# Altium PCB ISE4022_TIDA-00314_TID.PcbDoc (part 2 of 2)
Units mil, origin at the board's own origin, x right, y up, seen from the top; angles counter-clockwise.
Board outline 4724.41 x 1968.5 mil, 4 copper layers (Layer 1 - Top Layer, Layer 2 - GND, Layer 3 - Power, Layer 4 - Bottom Layer), stack 59 mil thick; 99 components, 62 nets, 309 pads, 290 vias.

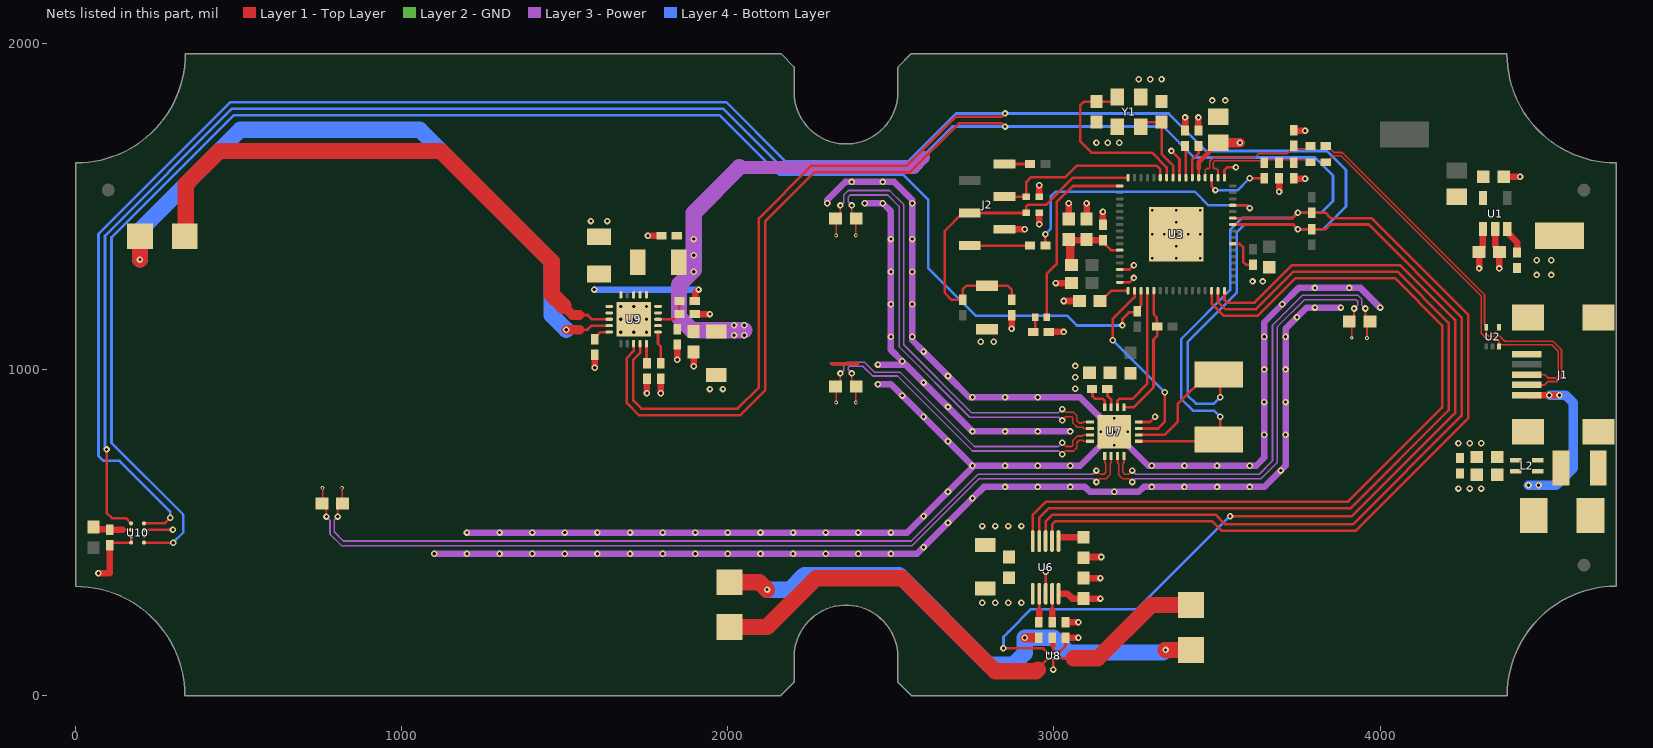
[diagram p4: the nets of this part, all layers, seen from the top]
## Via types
v1: diameter 20, hole 10, Layer 1 - Top Layer to Layer 4 - Bottom Layer, tented bottom, 252 vias
v2: diameter 19.68, hole 7.87, Layer 1 - Top Layer to Layer 4 - Bottom Layer, tented bottom, 18 vias
v3: diameter 12, hole 6, Layer 1 - Top Layer to Layer 4 - Bottom Layer, tented both sides, 17 vias
v4: diameter 20, hole 10, Layer 1 - Top Layer to Layer 4 - Bottom Layer, tented both sides, 3 vias

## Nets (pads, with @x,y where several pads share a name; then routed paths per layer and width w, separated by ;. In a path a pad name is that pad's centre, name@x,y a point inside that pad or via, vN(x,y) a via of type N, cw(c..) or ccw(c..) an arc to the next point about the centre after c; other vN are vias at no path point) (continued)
A1_TX: R8.1 U3.45 | length 849
  Layer 1 - Top Layer w8: R8.1@2973.62,1380 v1(2973.62,1415) ; U3.45@3548.23,1503.58 3591.42,1503.58 v1(3600,1495)
  Layer 4 - Bottom Layer w8: v1(2973.62,1415) 2990,1431.38 2990,1530 3005,1545 3431.72,1545 3473.45,1503.27 3591.73,1503.27 v1(3600,1495)
AVCC: C14.1 C15.2 C16.2 L4.1 U3.11 | length 254.7
  Layer 1 - Top Layer w8: C16.2@3149,1392.38 3149,1391 3174.21,1365.79 U3.11@3201.77,1365.79
  Layer 1 - Top Layer w20: C14.1@3046,1395.5 3047,1396.5 3101,1396.5 3101.13,1396.38 C16.2@3150,1396.38
  Layer 1 - Top Layer w25: C14.1@3046,1395.5 3050,1391.5 3050,1323.5 L4.1@3053.5,1320 ; C15.2@3100,1395.5 C15.2@3101,1396.5 ; C15.2@3101.13,1396.38 C15.2@3105.13,1392.38
B1_SCL: R6.1 SCL.1 U3.43 U6.2 U7.1 U9.18 U10.A1 | length 11230.3
  Layer 1 - Top Layer w8: v1(95,755) 95,560 111.11,543.89 154.57,543.89 U10.A1@170.32,528.14 ; U9.18@1711.06,1079.13 1711.06,1056.06 1690,1035 1690,896.72 1726.72,860 2038.28,860 2115,936.72 2115,1455 2265,1605 2558.28,1605 2708.28,1755 2840,1755 v1(2850,1745) ; U6.2@2994.06,473.75 2994.06,524.06 3005,535 3485,535 3515,505 3925,505 4270,850 4270,1168.28 3974.07,1464.21 3848.51,1464.21 3832,1480.72 R6.1@3790,1480.72 v1(3748,1480.72) 3731.49,1464.21 U3.43@3548.23,1464.21 ; U7.1@3259.8,779.81 SCL.1@3499.81,779.81 ; SCL.1@3505,785 3510,790 v1(3510,855)
  Layer 4 - Bottom Layer w8: v1(95,755) 90,760 90,1410 480,1800 1985,1800 2167,1618 2561.28,1618 2688.28,1745 v1(2850,1745) 3335,1745 3430,1650 3800,1650 3855.48,1594.52 3855.48,1516.21 3820,1480.72 v1(3748,1480.72) 3731.61,1464.34 3576.32,1464.34 3540,1428.02 3540,1243.02 3390.19,1093.21 3390.19,909.81 3426,874 3491,874 v1(3510,855)
B1_SDA: R7.1 SDA.1 U3.42 U6.3 U7.2 U9.19 U10.A2 | length 11518.1
  Layer 1 - Top Layer w8: U10.A2@209.69,528.14 273.14,528.14 v1(290,545) ; U9.19@1730.75,1079.13 1730.75,1050.75 1710,1030 1710,905 1735,880 2030,880 2095,945 2095,1463.28 2256.72,1625 2550,1625 2700,1775 2840,1775 v1(2850,1785) ; U6.3@2974.37,473.75 2974.37,534.37 2995,555 3495,555 3525,525 3916.72,525 4250,858.28 4250,1160 3965.47,1444.53 3846.56,1444.53 3832,1429.97 R7.1@3790,1429.97 v1(3748,1429.97) 3733.44,1444.53 U3.42@3548.23,1444.53 ; U7.2@3259.8,799.5 3339.5,799.5 3380,840 3380,895 3470,985 SDA.1@3505,985 3510,980 v1(3510,915)
  Layer 4 - Bottom Layer w8: v1(290,545) 290,565 135,720 85,720 70,735 70,1415 475,1820 1995,1820 2177,1638 2553,1638 2700,1785 v1(2850,1785) 3351.57,1785 3466.57,1670 3836.57,1670 3895.48,1611.09 3895.48,1500.48 3824.97,1429.97 v1(3748,1429.97) 3733.44,1444.53 3584.53,1444.53 3559.81,1419.81 3559.81,1234.81 3410,1085 3410,920 3435,895 3490,895 v1(3510,915)
D_N: J1.2 R9.1 U2.5 | length 1240.5
  Layer 1 - Top Layer w5.3: R9.1@3841,1682 3857.7,1665.3 3884.27,1665.3 4320.06,1229.51 4320.06,1139 4325.31,1133.74 U2.5@4325.31,1129.53 4325.31,1109.69 4333,1102 4367,1102 4382.7,1086.3 4530.27,1086.3 4556.3,1060.27 4556.3,975.73 4543.97,963.4 4515,963.4 4504.36,952.76 J1.2@4449.76,952.76
D_P: J1.3 R12.2 U2.3 | length 1222.2
  Layer 1 - Top Layer w5.3: R12.2@3838,1636 3857,1655 3880,1655 4309.76,1225.24 4309.76,1110.67 4328.73,1091.7 4360.3,1091.7 4364.69,1087.32 U2.3@4364.69,1070.47 ; U2.3@4365,1076 4526,1076 4546,1056 4546,980 4539.7,973.7 4515,973.7 4504.45,984.25 J1.3@4449.76,984.25
EN_05: U3.30 U6.5 | length 2593.6
  Layer 1 - Top Layer w8: U6.5@2935,473.75 2935,555 2975,595 3901.72,595 4190,883.28 4190,1135 4045,1280 3740,1280 3625,1165 3520,1165 3483.3,1201.7 U3.30@3483.3,1241.77
ERM_OUT-: ERM.- U8.A1 | length 1166.6
  Layer 1 - Top Layer w8: 2953.73,86.27 U8.A1@2981.62,114.17
  Layer 1 - Top Layer w50: ERM.-@2005,210.2 2120.2,210.2 2270,360 2535,360 2820,75 2945,75 2950,80
GND: C2.2 C3.1 C4.1 C5.1 C6.2 C7.2 C8.1 C9.2 C10.2 C11.1 C12.2 C13.2 C14.2 C15.1 C16.1 C17.2 C18.1 C19.1 C20.1 C21.2 C22.1 C24.1 C26.1 C27.1 C29.1 C32.2 C33.1 C34.2 C35.1 C36.1 C37.2 C38.1 C39.1 J2.5 L3.2 R10.1 R13.1 R20.1 R21.2 S1.1 U1.2 U3.14 U3.16 U3.39 U3.49 U3.56 U3.65 U4.2 U5.2 U6.8 U7.4 U7.8 U7.17 U8.B1 U9.4 U9.5 U9.6 U9.21 U10.B2 U10.C1 U10.D1 Y1.2 Y1.4 | length 12582.4
  Layer 1 - Top Layer w8: C38.1@105,461.38 112.71,469.09 U10.D1@170.32,469.09 U10.C1@170.32,488.77 ; U10.B2@209.69,508.46 v1(298.46,508.46) ; U6.8@2974.37,312.33 v1(2974.37,380) ; v1(2997.37,80) U8.B1@2997.37,114.17 ; C27.1@3117,939.17 C27.1@3117.17,939.34 ; C27.1@3118,939.17 3118,918 3126,910 3150,910 3155.47,904.53 U7.8@3155.47,884.14 ; U3.16@3201.77,1267.36 3231.73,1267.36 v1(3245,1280.63) ; U3.14@3201.77,1306.73 3231.73,1306.73 v1(3245,1320) ; U7.4@3259.8,838.87 3293.87,838.87 v1(3310,855) ; v1(3360,1670) 3384.85,1645.15 U3.56@3384.85,1588.23 ; U3.49@3522.68,1588.23 3522.68,1611.68 3531,1620 v1(3558,1620) ; U3.39@3548.23,1385.47 3569.53,1385.47 3580,1375 3580,1330 3588.62,1321.38 C19.1@3610,1321.38
  Layer 1 - Top Layer w10: 2318,1017 2398,1017 ; 2318,1018 2398,1018
  Layer 1 - Top Layer w20: v1(70,375) 105,375 C38.1@105,461.38 ; v1(1592.06,1005) R21.2@1592.06,1045.31 ; v1(1751.85,926.85) C36.1@1751.85,971.6 ; v1(1755,1410) C32.2@1796.38,1410 ; v1(1793.85,926.85) C39.1@1793.85,971.6 ; v1(1845,1030) C35.1@1845,1076.38 ; v1(1895,1010) C34.2@1895,1053.5 ; R20.1@1898.62,1170 v1(1945,1170) ; J2.5@2848.15,1430 v1(2910,1430) ; v1(2870,1125) C11.1@2870,1166.38 ; U4.2@2954.68,1531 v1(2954.68,1564.68) ; v1(2955,1445) U5.2@2955,1479.68 ; R10.1@2983.62,1115 v1(3030,1115) ; v1(3005,1265) C18.1@3053.5,1265 ; v1(3030,1210) C10.2@3078.5,1210 ; C29.1@3035.37,224.67 v1(3075,224.67) ; C14.2@3045,1461.5 v1(3045,1510) ; C22.1@3090.37,360.54 v1(3142.55,360.54) ; C24.1@3090.37,422.55 3092.83,425 v1(3145,425) ; C15.1@3100,1461.5 v1(3100,1510) ; C16.1@3150,1443.62 v1(3150,1484) ; U7.17@3163.74,831.26 3163.74,836.34 3196.18,836.34 3212,820.52 U7.17@3212,809.34 ; C9.2@3402,1732.62 v1(3402,1773) ; C13.2@3443,1732.62 v1(3443,1773) ; v1(3690,1545) R13.1@3690,1586.38 ; C7.2@3735,1586.38 3736.38,1585 v1(3770,1585) ; C6.2@3735,1733.62 3736.38,1732.24 v1(3770,1732.24) ; U1.2@4352.8,1430.78 4352.8,1377.2 4366.5,1363.5 C4.1@4366.5,1360 4365,1358.5 v1(4365,1310) ; C3.1@4379.3,1591.03 v1(4428.97,1591.03)
  Layer 3 - Power w20: v1(1100,435) v1(1200,435) v1(1300,435) v1(1400,435) v1(1500,435) v1(1600,435) v1(1700,435) v1(1800,435) v1(1900,435) v1(2000,435) v1(2100,435) v1(2200,435) v1(2300,435) v1(2400,435) v1(2500,435) 2580,435 v1(2600,455) v1(2675,530) v1(2750,605) 2785,640 v1(2850,640) v1(2950,640) v1(3050,640) 3095,640 3110,625 v1(3185,625) 3260,625 3275,640 v1(3300,640) v1(3400,640) v1(3500,640) v1(3600,640) 3645,640 v1(3695,690) 3710,705 v1(3710,800) v1(3710,900) v1(3710,1000) v1(3710,1100) 3710,1125 v1(3745,1160) 3775,1190 v1(3800,1190) v1(3880,1190) ; v1(1200,500) v1(1300,500) v1(1400,500) v1(1500,500) v1(1600,500) v1(1700,500) v1(1800,500) v1(1900,500) v1(2000,500) v1(2100,500) v1(2200,500) v1(2300,500) v1(2400,500) v1(2500,500) 2550,500 v1(2600,550) v1(2675,625) 2755,705 v1(2850,705) v1(2950,705) v1(3050,705) 3080.66,705 v2(3185,809.34) 3289.34,705 v1(3300,705) v1(3400,705) v1(3500,705) v1(3600,705) 3620,705 3645,730 v1(3645,800) v1(3645,900) v1(3645,1000) v1(3645,1100) 3645,1145 v1(3700,1200) 3750,1250 v1(3800,1250) v1(3905,1250) 3940,1250 v1(4000,1190) ; v1(2305,1510) 2305,1520 2360,1575 v1(2380,1575) v1(2475,1575) 2510,1575 2565,1520 v1(2565,1510) v1(2565,1400) v1(2565,1300) v1(2565,1200) v1(2565,1100) 2565,1090 v1(2600,1055) v1(2675,980) 2740,915 v1(2750,915) v1(2850,915) v1(2950,915) 3080,915 v2@3185.33,809.67 ; v1(2420,1510) v1(2475,1510) 2500,1485 v1(2500,1400) v1(2500,1300) v1(2500,1200) v1(2500,1100) 2500,1060 v1(2535,1025) 2545,1015 ; v1(2460,955) 2500,955 v1(2535,920) v1(2600,855) v1(2675,780) v1(2750,705) ; v1(2460,1015) 2545,1015 ; v1(3050,810) v1(2950,810) v1(2850,810) v1(2750,810) v1(2675,885) v1(2600,960) 2545,1015
  Layer 2 - GND w10: 2325,1017 2395,1017 ; 2325,1018 2395,1018
  Layer 4 - Bottom Layer w10: 2317,1018 2397,1018
  other v1: 2780,520 2820,520 2860,520 2900,520 4240,774 4275,774 4310,774 1945,940 1985,940 3065.5,941 3065.5,976 3065.5,1011 2775,1085 2815,1085 1671.69,1114.57 1711.06,1114.57 1750.43,1114.57 1671.69,1153.94 1711.06,1153.94 1750.43,1153.94 1671.69,1193.31 1711.06,1193.31 1750.43,1193.31 3609,1270 3640,1270 1580,1455 1630,1455 3130,1695 3165,1695 3200,1695 3485,1825 3525,1825 3260,1890 3295,1890 3330,1890
  other v2: 3185,768 3143.66,809.34 3226.34,809.34 3185,850.68 3301.18,1341.18 3375,1341.18 3448.82,1341.18 3375,1378.09 3301.18,1415 3338.09,1415 3375,1415 3411.91,1415 3448.82,1415 3375,1451.91 3301.18,1488.82 3375,1488.82 3448.82,1488.82
IN0A: C30.1 U7.9 | length 1462.1
  Layer 1 - Top Layer w5: v3(2332.2,1411.16) 2332.2,1461.3 C30.1@2330.5,1463 2345,1477.5 v1(2345,1503) ; v1(3025,878.68) 3035,868.68 3060,868.68 3070,858.68 3070,843.48 3077.77,835.71 3087.03,835.71 3090.19,838.87 U7.9@3110.2,838.87
  Layer 3 - Power w5: v1(2345,1503) 2355,1513 2355,1534.8 2369.2,1549 2495.8,1549 2539,1505.8 2539,1076 2747.32,867.68 3014,867.68 v1(3025,878.68)
IN0B: C30.2 U7.10 | length 1438.4
  Layer 1 - Top Layer w5: v1(2380,1503) 2380,1476.5 C30.2@2393.5,1463 2392.2,1461.71 v3(2392.2,1411.16) ; v1(3025,843.68) 3036,854.68 3054,854.68 3058,850.68 3058,835.68 3070.97,822.71 3086.66,822.71 3090.19,819.18 U7.10@3110.2,819.18
  Layer 3 - Power w5: v1(2380,1503) 2369,1514 2369,1529 2375,1535 2490,1535 2525,1500 2525,1070.2 2741.52,853.68 3015,853.68 v1(3025,843.68)
IN1A: C28.1 U7.11 | length 1019.8
  Layer 1 - Top Layer w5: C28.1@2330.5,948 2345,962.5 v1(2345,988) ; v3(2332.2,899.35) C28.1@2332.2,946.3 ; v1(3025,775) 3036,764 3054,764 3058,768 3058,783 3070.97,795.97 3086.66,795.97 3090.19,799.5 U7.11@3110.2,799.5
  Layer 3 - Power w5: v1(2345,988) 2355,998 2355,1011.8 2365.2,1022 2418.97,1022 2448.97,992 2528,992 2756,764 3014,764 v1(3025,775)
IN1B: C28.2 U7.12 | length 998.2
  Layer 1 - Top Layer w5: v1(2380,988) 2380,961.5 C28.2@2393.5,948 ; v3(2392.2,899.35) C28.2@2392.2,946.71 ; v1(3025,740) 3035,750 3060,750 3070,760 3070,775.2 3077.77,782.97 3087.03,782.97 3090.19,779.81 U7.12@3110.2,779.81
  Layer 3 - Power w5: v1(2380,988) 2369,999 2369,1006 2373,1010 2414,1010 2444,980 2520.2,980 2750.2,750 3015,750 v1(3025,740)
IN2A: C25.1 U7.13 | length 2671.4
  Layer 1 - Top Layer w5: v1(804,549) 804,574.5 C25.1@818.5,589 817.4,590.09 v3(817.4,637.25) ; v1(3130,690) 3141,679 3153,679 3159,685 3159,711 3155.47,714.53 U7.13@3155.47,734.54
  Layer 3 - Power w5: v1(804,549) 793,538 793,502 821,474 2562.03,474 2767.03,679 3119,679 v1(3130,690)
IN2B: C25.2 U7.14 | length 2716.7
  Layer 1 - Top Layer w5: v3(757.4,637.25) 757.4,590.9 C25.2@755.5,589 769,575.5 v1(769,549) ; v1(3130,655) 3140,665 3160,665 3172,677 3172,711.37 3175.16,714.53 U7.14@3175.16,734.54
  Layer 3 - Power w5: v1(769,549) 780,538 780,495 815,460 2565,460 2770,665 3120,665 v1(3130,655)
IN3A: C31.1 U7.15 | length 1403.6
  Layer 1 - Top Layer w5: U7.15@3194.84,734.54 3194.84,714.53 3198.37,711 3198.37,676.63 3210,665 3230,665 v1(3240,655) ; v3(3913.01,1097.25) 3913.01,1139.5 C31.1@3905.5,1147 3920,1161.5 v1(3920,1187)
  Layer 3 - Power w5: v1(3240,655) 3250,665 3634.8,665 3684,714.2 3684,1130 3768,1214 3926,1214 3931,1209 3931,1198 v1(3920,1187)
IN3B: C31.2 U7.16 | length 1404.8
  Layer 1 - Top Layer w5: U7.16@3214.53,734.54 3214.53,714.53 3211.37,711.37 3211.37,684.63 3217,679 3229,679 v1(3240,690) ; v1(3955,1187) 3955,1160.5 C31.2@3968.5,1147 3959.88,1138.38 v3(3959.88,1096.12)
  Layer 3 - Power w5: v1(3240,690) 3251,679 3629,679 3670,720 3670,1135.8 3762.2,1228 3932,1228 3944,1216 3944,1198 v1(3955,1187)
IN_SW: U3.32 U8.A2 | length 2989.4
  Layer 1 - Top Layer w8: v1(2845,145) 2966.54,145 2981.54,130 U8.A2@2981.62,129.92 ; U3.32@3522.68,1241.77 3522.68,1212.32 3530,1205 3615,1205 3730,1320 4061.57,1320 4230,1151.57 4230,866.72 3913.28,550 v1(3540,550)
  Layer 4 - Bottom Layer w8: v1(2845,145) 2845,180 2860,195 2930,265 3255,265 v1(3540,550)
IN_TRIG_05: U3.31 U6.4 | length 2594.8
  Layer 1 - Top Layer w8: U6.4@2954.69,473.75 2954.69,544.69 2985,575 3910,575 4210,875 4210,1143.28 4053.28,1300 3735,1300 3620,1185 3525,1185 3502.99,1207.01 U3.31@3502.99,1241.77
LDC_CLKIN: U3.18 U7.3 | length 584.6
  Layer 1 - Top Layer w8: v1(3180,1090) 3180,1155 3247.02,1222.02 U3.18@3247.02,1241.77 ; U7.3@3259.8,819.18 3319.18,819.18 3340,840 v1(3340,930)
  Layer 4 - Bottom Layer w8: v1(3180,1090) v1(3340,930)
LDC_INTB: R4.1 U3.21 U7.5 | length 424.3
  Layer 1 - Top Layer w8: U7.5@3214.53,884.14 3244.14,884.14 3305,945 3305,1091.65 3316.38,1103.03 R4.1@3316.38,1131.65 R4.1@3315,1130.28 ; U3.21@3305,1240.69 U3.21@3306.09,1241.77 3306.09,1168.91 3315,1160 R4.1@3315,1131.65
LDC_SD: U3.20 U7.6 | length 418.8
  Layer 1 - Top Layer w8: U7.6@3194.84,884.14 3194.84,904.53 3200.31,910 3240,910 3286.4,956.4 U3.20@3286.4,1241.77
LRA_OUT-: LRA.- U8.C1 | length 432.3
  Layer 1 - Top Layer w8: U8.C1@3013.12,114.17 3060,114.17
  Layer 1 - Top Layer w50: 3060,114.17 3134.17,114.17 3297.8,277.8 3377.63,277.8
MSP_D_N: C6.1 R9.2 U3.52 | length 388
  Layer 1 - Top Layer w5.3: U3.52@3463.61,1588.23 3463.61,1611.61 3468,1616 3475,1616 3478,1619 3478,1638.57 3489.43,1650 3615,1650 3627,1662 3714,1662 3729,1677 3778.38,1677 R9.2@3786.38,1685
MSP_D_P: C7.1 R11.2 R12.1 R13.2 U3.50 | length 366
  Layer 1 - Top Layer w5.3: U3.50@3502.99,1588.23 3502.99,1611.61 3498.59,1616 3491.59,1616 3488.59,1619 3488.59,1634.59 3493.7,1639.7 3638.92,1639.7 R11.2@3645,1633.62 3654.38,1643 3778.38,1643 R12.1@3786.38,1635
NDRDY_HDC: R3.1 U3.19 U10.D2 | length 4911.2
  Layer 1 - Top Layer w8: U10.D2@209.69,469.09 v1(299.09,469.09) ; v1(3210,1135) 3210,1155 3230,1175 3251.38,1175 R3.1@3255,1178.62 ; R3.1@3255,1185 3266.71,1196.71 U3.19@3266.71,1241.77
  Layer 4 - Bottom Layer w8: v1(299.09,469.09) 330,500 330,555 110,775 110,1405 485,1780 1975,1780 2157,1598 2537,1598 2615,1520 2615,1310 2760,1165 3040,1165 3070,1135 v1(3210,1135)
NetC3_2: C3.2 R1.1 U1.5
NetC24_2: C24.2 U6.1 | length 72.4
  Layer 1 - Top Layer w20: U6.1@3018,485.54 C24.2@3090.37,485.54
NetC26_2: C26.2 C27.2 L6.2 U7.7 | length 60.5
  Layer 1 - Top Layer w8: C27.2@3164,940 3164,919.38 3175.16,908.22 U7.7@3175.16,884.14
NetC36_2: C36.2 U9.20 | length 60.9
  Layer 1 - Top Layer w8: U9.20@1750.43,1079.13 1750.43,1020.26 C36.2@1751.85,1018.84
NetC37_1: C37.1 R19.2 U9.10 U9.11 U9.12 | length 360.5
  Layer 1 - Top Layer w8: R19.2@1898.62,1210 R19.2@1900,1210
  Layer 1 - Top Layer w20: R19.2@1900,1210 1900,1235 v1(1910,1245)
  Layer 4 - Bottom Layer w20: v1(1590,1245) v1(1910,1245)
NetC38_2: C38.2 L7.1 U10.B1 | length 118.8
  Layer 1 - Top Layer w8: 145,508.46 U10.B1@170.32,508.46
  Layer 1 - Top Layer w20: L7.1@55,517.48 62.48,510 103.62,510 C38.2@105,508.62 ; C38.2@105.17,508.46 145,508.46
NetC39_2: C39.2 U9.1 | length 99
  Layer 1 - Top Layer w8: U9.1@1785.87,1114.57 1785.87,1079.13 1793.85,1071.15 C39.2@1793.85,1018.84
NetD2_1: D2.1 U3.1 | length 579.9
  Layer 1 - Top Layer w8: D2.1@2977.72,1160 2977.72,1292.72 3008,1323 3008,1513 3057.64,1562.64 U3.1@3201.77,1562.64
NetD2_2: D2.2 R10.2 | length 47.4
  Layer 1 - Top Layer w8: R10.2@2936.38,1115 2942.28,1120.91 D2.2@2942.28,1160
NetJ2_1: J2.1 R5.2 | length 78.2
  Layer 1 - Top Layer w8: J2.1@2848.15,1630 R5.2@2926.38,1630
NetJ2_6: J2.6 R8.2 | length 184.5
  Layer 1 - Top Layer w8: J2.6@2741.85,1380 R8.2@2926.38,1380
NetL1_1: L1.1 L2.2
NetL2_3: L2.3 L3.1
NetL5_1: L5.1 U9.7 U9.8
NetR2_1: R2.1 U1.3 | length 84.5
  Layer 1 - Top Layer w8: U1.3@4390.21,1419.79 U1.3@4390.21,1430.78
  Layer 1 - Top Layer w20: U1.3@4390.21,1419.79 4420,1390 R2.1@4420,1358.62
NetR15_1: R15.1 U6.7 | length 89.2
  Layer 1 - Top Layer w8: R15.1@2953.37,224.67 R15.1@2954.69,225.98 ; 2954.69,260.94 U6.7@2954.69,312.33
  Layer 1 - Top Layer w20: R15.1@2954.69,224.98 2954.69,225.98 2954.69,260.94
NetR18_1: R18.1 U6.9 | length 87.4
  Layer 1 - Top Layer w8: 2994.06,260.94 U6.9@2994.06,312.33
  Layer 1 - Top Layer w20: R18.1@2994.06,224.98 2994.06,260.94
NetR19_1: R19.1 R20.2 U9.3 | length 103.7
  Layer 1 - Top Layer w8: U9.3@1785.87,1153.94 1833.94,1153.94 R20.2@1845,1165 ; R20.2@1851.38,1170 R19.1@1851.38,1210
NetR21_1: R21.1 U9.15 | length 57.9
  Layer 1 - Top Layer w8: R21.1@1592.06,1090.57 R21.1@1592.06,1092.56 1592.06,1097.06 1609.57,1114.57 U9.15@1636.26,1114.57
OUT+_05: ERM.+ LRA.+ R15.2 | length 1681.1
  Layer 1 - Top Layer w30: v1(2910,177.42) R15.2@2950,177.42
  Layer 1 - Top Layer w50: ERM.+@2005,348 2097,348 v1(2120,325) ; v1(3342,140) LRA.+@3420,140
  Layer 4 - Bottom Layer w50: v1(2120,325) 2190,325 2235,370 2525,370 2800,95 2875,95 2910,130 v1(2910,177.42) 2998.33,177.42 3043.75,132 3334,132 v1(3342,140)
OUT+_67: Piezo.+ U9.13 | length 1774.7
  Layer 1 - Top Layer w8: 1545.06,1166.94 1570.06,1166.94 1583.06,1153.94 U9.13@1636.26,1153.94
  Layer 1 - Top Layer w30: 1495,1195 1523.06,1166.94 1545.06,1166.94
  Layer 1 - Top Layer w50: Piezo.+@337.68,1406.32 337.68,1567.68 440,1670 1120,1670 1460,1330 1460,1230 1495,1195
OUT-_05: R18.2 U8.B2 | length 48.7
  Layer 1 - Top Layer w8: U8.B2@2997.37,129.92 2997.37,151.63
  Layer 1 - Top Layer w15: R18.2@2994.37,177.42 2997.37,174.42 2997.37,151.63
OUT-_67: Piezo.- U9.14 | length 2083.2
  Layer 1 - Top Layer w8: 1545.06,1121.94 1570.06,1121.94 1582.38,1134.25 U9.14@1636.26,1134.25
  Layer 1 - Top Layer w30: v1(1504.42,1121.94) 1545.06,1121.94
  Layer 1 - Top Layer w50: v1(197.2,1337.2) Piezo.-@197.2,1409
  Layer 4 - Bottom Layer w50: v1(197.2,1337.2) 197.2,1427.2 505,1735 1055,1735 1460,1330 1460,1166.36 v1(1504.42,1121.94)
PUR: R11.1 U3.51 | length 208.1
  Layer 1 - Top Layer w8: U3.51@3483.3,1588.23 3483.3,1561.7 v1(3495,1550) ; v1(3600,1586.38) R11.1@3645,1586.38
  Layer 4 - Bottom Layer w8: v1(3495,1550) 3563.62,1550 v1(3600,1586.38)
SBWTCK: J2.3 U3.59 U4.1 | length 575.6
  Layer 1 - Top Layer w8: J2.3@2846.54,1529.99 U4.1@2915.32,1530 2915.3,1575.3 2930,1590 3035,1590 3070,1625 3315,1625 3325.78,1614.22 U3.59@3325.78,1588.23
SBWTDIO: C11.2 J2.4 R14.1 S1.2 U3.64 U5.1 | length 1118.3
  Layer 1 - Top Layer w8: C11.2@2870,1213.62 2870,1245 2858.07,1256.93 S1.2@2795,1256.93 2731.93,1256.93 2720,1245 R14.1@2720,1213.62 2686.38,1213.62 2665,1235 2665,1425 2720,1480 J2.4@2741.85,1480 U5.1@2915.32,1480 2915.32,1500.32 2920,1505 2975,1505 3058.23,1588.23 U3.64@3227.33,1588.23
USB_GND: C1.2 D1.1 J1.5 J1.6 J1.7 J1.8 J1.9 L2.4 U2.4
V18: C9.1 U3.55 | length 98.2
  Layer 1 - Top Layer w8: C9.1@3402,1685.38 3404.54,1682.84 U3.55@3404.54,1588.23
VBUS: C1.1 D1.2 J1.1 L2.1 | length 541.4
  Layer 1 - Top Layer w20: J1.1@4449.76,921.26 4520,921.26 v1(4550,921.26)
  Layer 4 - Bottom Layer w30: v1(4455,645) 4485,645 4539.31,645 4592.5,698.18 4592.5,897.5 4568.74,921.26 v1(4550,921.26) v1@4520,921.26
  other v1: 4486,645 4519,921.26
VBUS_FLT: C2.1 C4.2 C12.1 C20.2 C21.1 C22.2 C29.2 C32.1 C33.2 C34.1 C35.2 L1.2 L5.2 R2.2 U1.1 U3.53 U6.6 U6.10 U8.C2 U9.2 VBUS_FLT.1 | length 1870
  Layer 1 - Top Layer w8: U8.C2@3013.12,129.92 3035.37,152.17 C29.2@3035.37,177.42 ; U6.10@3013.74,312.33 U6.10@3014.41,313 ; U3.53@3443.92,1588.23 3443.92,1616.92
  Layer 1 - Top Layer w15: 3443.92,1616.92 3443.92,1635.92 3503,1695 C12.1@3504,1695
  Layer 1 - Top Layer w20: U6.10@3018,313 3041,313 3056.45,297.55 C22.2@3090.37,297.55 v1(3142.45,297.55) ; C29.2@3035.37,177.42 v1(3075,177.42) ; v1(4303.5,1310) C4.2@4303.5,1360 ; C4.2@4310,1370 4315.4,1375.4 U1.1@4315.4,1430.78
  Layer 1 - Top Layer w30: C12.1@3504,1695 v1(3570,1695)
  Layer 3 - Power w40: 2035,1620 2570,1620 2600,1650
  Layer 3 - Power w50: 2035,1620 1895,1480 v1(1895,1400) v1(1895,1350) 1895,1305 1850,1260 1850,1160 1890,1120 2050,1120
  other v1: 2780,285 2820,285 2860,285 2900,285 4240,635 4275,635 4310,635 2019,1105 2050,1105 2019,1136 2050,1136 4480,1290 4525,1290 1895,1300 4480,1335 4525,1335
VCORE: C10.1 U3.17 | length 81.3
  Layer 1 - Top Layer w8: C10.1@3155,1220 3176.77,1241.77 U3.17@3227.33,1241.77
VUSB: C13.1 U3.54 | length 104.9
  Layer 1 - Top Layer w8: U3.54@3424.23,1588.23 3424.23,1644.23 3443,1663 C13.1@3443,1685.38
XT2IN: C5.2 U3.57 Y1.1 | length 254.1
  Layer 1 - Top Layer w8: Y1.1@3266.42,1744.72 3280.2,1758.5 C5.2@3330,1758.5 3330,1660 3365.16,1624.84 U3.57@3365.16,1588.23
XT2OUT: C8.2 U3.58 Y1.3 | length 564.2
  Layer 1 - Top Layer w8: Y1.3@3193.58,1835.28 3179.8,1821.5 C8.2@3130,1821.5 3091.5,1821.5 3080,1810 3080,1700 3115,1665 3300,1665 3345.47,1619.53 U3.58@3345.47,1588.23
pads on no net: FID1.1 FID2.1 FID3.1 J1.4 U1.4 U2.1 U2.2 U3.2 U3.3 U3.4 U3.5 U3.6 U3.7 U3.8 U3.9 U3.10 U3.12 U3.13 U3.22 U3.23 U3.24 U3.25 U3.26 U3.27 U3.28 U3.29 U3.33 U3.34 U3.35 U3.36 U3.37 U3.38 U3.41 U3.44 U3.47 U3.48 U3.60 U3.61 U3.62 U3.63 U9.9 U9.16 U9.17 U10.C2
copper on no net:
  other v3: 2362.2,709.35 2362.2,739.35 2362.2,899.35 3937.01,969.25 3937.01,991.25 3937.01,1099.25 2362.2,1221.16 2362.2,1251.16 2362.2,1411.16
  other v4: 787.4,651.25 787.4,973.25 787.4,1003.25

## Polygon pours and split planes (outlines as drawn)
GND on Layer 2 - GND "Layer 2 - GND- GND" (solid, remove dead copper, pour order 13): 0,0 4724.41,0 4724.41,1967.91 4725,1968.5 -0.5,1968.5 -1,1969
GND on Layer 3 - Power "Layer 2 - GND- GND" (solid, remove dead copper, pour order 12): 0,0 4724.41,0 4724.41,1967.91 4725,1968.5 -0.5,1968.5 -1,1969
VBUS_FLT on Layer 3 - Power "Layer 3 - Power- VBUS_FLT" (solid, pour order 9): 2765,280 2765,320 2785,340 2980,340 3015,375 3040,400 3175,400 3195,420 3210,435 3240,435 3840,435 3900,495 4275,870 4275,945 4275,1565 4180,1660 4155,1685 3920,1685 3500,1685 3440,1625 2580,1625 2580,1740 2660,1820 2705,1865 4230,1865 4455,1640 4595,1500 4595,1105 4595,845 4380,630 3915,165 3215,165 3025,165 2980,210 2785,210 2765,230 2765,280 2765,320
GND on Layer 1 - Top Layer "Layer 2 - GND- GND" (solid, remove dead copper, pour order 11): 0,0 4724.41,0 4724.41,1967.91 4725,1968.5 -0.5,1968.5 -1,1969
GND on Layer 4 - Bottom Layer "Layer 2 - GND- GND" (solid, remove dead copper, pour order 10): 0,0 4724.41,0 4724.41,1967.91 4725,1968.5 -0.5,1968.5 -1,1969

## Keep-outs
Keep-Out Layer:
  lines w4: 2161.42,0 335.17,0 ccw(c0.52,0) 0,334.65 0,1633.36 ccw(c1.52,1968) 336.17,1968.5 2162.5,1968.5 2203.15,1927.85 2203.15,1850.39 ccw(c2362.2,1850.39) 2521.26,1850.39 2521.26,1927.26 2562.5,1968.5 4388.83,1968.5 ccw(c4723.48,1968) 4724.41,1633.36 ; 2162,0 2203.15,41.15 2203.15,118.11 cw(c2362.2,118.11) 2521.26,118.11 2521.26,40.74 2562,0 4389.84,0 cw(c4724.48,1) 4724.41,335.65
  text ".Layer_Name" at 577,-858.49 h60

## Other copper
Layer 1 - Top Layer:
  region: 182,532 198,532 198,465 182,465
  region net VBUS_FLT: 4405,1330 4450,1330 4470,1350 4470,1455 4630,1455 4630,1320 4575,1265 4425,1265 4405,1285
  region net GND: 1745,1241 1776,1241 1798,1219 1798,1168 1745,1168
  pour cut-out: 2913.35,357.61 2913.35,428.48 3033.48,428.48 3035,430 3035.4,429.6 3035.4,357.61
  pour cut-out: 3160,1790 3295,1790 3295,1810 3245,1810 3245,1875 3230,1875 3230,1810 3160,1810
  pour cut-out: 3175,1215 3575,1215 3575,1595 3175,1595
  pour cut-out: 1615,1085 1810,1085 1810,1270 1615,1270
  pour cut-out: 2238,1023 2238,1027 2482,1027 2482,1453 2242,1453 2242,1027 2238,1027 2238,1457 2486,1457 2486,1023 2459,1023 2254,1023 2242,1023
  pour cut-out: 2238,511.19 2238,515.19 2482,515.19 2482,941.19 2242,941.19 2242,515.19 2238,515.19 2238,945.19 2486,945.19 2486,511.19 2459,511.19 2254,511.19 2242,511.19
  pour cut-out: 325,410 325,470 290,505 290,515 310,535 310,560 275,595 45,595 45,410
  region net VBUS_FLT: 1825,1285 1910,1285 1910,1425 1825,1425
  region net GND: 1645,1380 1645,1470 1565,1470 1565,1380
  region net VBUS_FLT: 1774,1140 2060,1140 2060,1095 1875,1095 1865,1105 1830,1105 1806,1129 1774,1129
  region net GND: 1930,1005 1930,925 2000,925 2000,1005
  region net NetL5_1: 1706,1217 1706,1253 1695,1264 1695,1369 1747,1369 1747,1264 1736,1253 1736,1217
  region net NetC37_1: 1648,1169 1648,1211 1654,1217 1677,1217 1677,1288 1645,1320 1565,1320 1565,1199 1595,1169
  region net GND: 2915,400 2915,525 2905,535 2775,535 2755,515 2755,425 2780,400
  region net VBUS_FLT: 2908,385 2941,352 2941,282 2929,270 2765,270 2755,280 2755,360 2780,385
  region net GND: 3135,925 3135,1015 3050,1015 3050,925 3112.05,925 3114,923.05 3122.03,923.05 3124.03,925
  region net NetC26_2: 3145,925 3158,925 3160,923 3168,923 3170,925 3210,925 3254,969 3254,1015 3145,1015
  region net 3V3: 3095,1340 3160,1340 3175,1325 3175,1297 3182,1290 3182,1284 3175,1277 3175,1260 3160,1245 3095,1245
  region net GND: 3595,1340 3680,1340 3680,1295 3645,1260 3605,1260 3595,1270 3595,1307 3595,1310 3595,1311 3595,1313 3595,1316 3593,1318 3593,1325 3595,1327 3595,1328
  region net 3V3: 3580,1402 3597,1385 3597,1352 3680,1352 3680,1415 3667,1428 3599,1428 3580,1409
  region net GND: 2830,1140 2760,1140 2760,1070 2830,1070
  region net GND: 3350,1800 3245,1800 3245,1900 3335,1900 3350,1885
  region net GND: 3110,1780 3215,1780 3215,1680 3125,1680 3110,1695
  region net GND: 3470,1750 3540,1750 3540,1835 3470,1835
  region net USB_GND: 4695,495 4695,745 4720,770 4720,1200 4395,1200 4355,1160 4355,1115 4540,1115 4580,1075 4580,920 4555,895 4390,895 4375,910 4375,1019 4393,1037 4496,1037 4496,1060 4380,1060 4365,1045 4355,1045 4330,1045 4310,1025 4310,990 4310,850 4395,765 4425,765 4455,735 4455,710 4510,710 4510,750 4525,765 4585,765 4600,750 4600,495
  region net VBUS: 4455,700 4520,700 4525,705 4525,752 4581,752 4581,551 4525,495 4425,495 4425,650 4455,680
  region net NetL2_3: 4440,710 4440,735 4420,755 4335,755 4335,710
  region net NetL1_1: 4440,700 4335,700 4335,655 4415,655 4440,680
  region net VBUS_FLT: 4320,700 4320,625 4310,615 4240,615 4230,625 4230,700
  region net GND: 4320,709 4320,784 4310,794 4240,794 4230,784 4230,709
  region net NetC3_2: 4200,1500 4330,1500 4340,1510 4340,1615 4295,1615 4295,1580 4275,1560 4200,1560
  region net 3V3: 4270,1585 4040,1585 4000,1625 4000,1760 4225,1760 4270,1715
  text ".Layer_Name" at 577,-858.49 h60
Layer 3 - Power:
  region net GND: 2490,1065 2490,1025 2530,1025
  pour cut-out: 325,410 325,470 290,505 290,515 310,535 310,560 275,595 45,595 45,410
  pour cut-out: 2238,1023 2238,1027 2482,1027 2482,1453 2242,1453 2242,1027 2238,1027 2238,1457 2486,1457 2486,1023 2459,1023 2254,1023 2242,1023
  pour cut-out: 2238,511.19 2238,515.19 2482,515.19 2482,941.19 2242,941.19 2242,515.19 2238,515.19 2238,945.19 2486,945.19 2486,511.19 2459,511.19 2254,511.19 2242,511.19
Layer 2 - GND:
  pour cut-out: 325,410 325,470 290,505 290,515 310,535 310,560 275,595 45,595 45,410
  pour cut-out: 2238,511.19 2238,515.19 2482,515.19 2482,941.19 2242,941.19 2242,515.19 2238,515.19 2238,945.19 2486,945.19 2486,511.19 2459,511.19 2254,511.19 2242,511.19
  pour cut-out: 2238,1023 2238,1027 2482,1027 2482,1453 2242,1453 2242,1027 2238,1027 2238,1457 2486,1457 2486,1023 2459,1023 2254,1023 2242,1023
Layer 4 - Bottom Layer:
  pour cut-out: 2238,1023 2238,1027 2482,1027 2482,1453 2242,1453 2242,1027 2238,1027 2238,1457 2486,1457 2486,1023 2459,1023 2254,1023 2242,1023
  pour cut-out: 2238,511.19 2238,515.19 2482,515.19 2482,941.19 2242,941.19 2242,515.19 2238,515.19 2238,945.19 2486,945.19 2486,511.19 2459,511.19 2254,511.19 2242,511.19
  pour cut-out: 325,410 325,470 290,505 290,515 310,535 310,560 275,595 51,595 51,410
  text ".Layer_Name" at 577,-858.49 h60

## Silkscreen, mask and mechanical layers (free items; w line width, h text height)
Top Overlay:
  circle w12: c4180,379 r196.85
  lines w7.01: 373,1511 2123.13,1511 ; 373,1512 373,1738.54 ; 374,1738.27 2123.13,1738.27 2123.13,1512 ; 922.56,144.2 922.56,419.8 1867.44,419.8 1867.44,144.2 922.56,144.2
  text "For evaluation only; not FCC approved for resale" at 567,1830 h75
  text ".TID" at 1385,25 h100
  text ".PRJ_Number" at 3224,25 h100
  text ".PCB_Rev" at 3610,25 h100
  text ".Layer_Name" at 577,-858.49 h60
Bottom Overlay:
  text ".Layer_Name" at 577,-858.49 h60
Top Paste:
  text ".Layer_Name" at 577,-858.49 h60
Bottom Paste:
  text ".Layer_Name" at 577,-858.49 h60
Top Solder:
  text ".Layer_Name" at 577,-858.49 h60
  text ".Layer_Name" at 577,-858.49 h60
Bottom Solder:
  lines w100: 0,334.65 cw(c0.52,0) 335.17,0 2161.42,0 ; 0,1633.36 ccw(c1.52,1968) 336.17,1968.5 ; 0.76,335.4 0.76,1632.99 ; 336.54,1968.5 2162.5,1968.5 2203.15,1927.85 2203.15,1850.39 ccw(c2362.2,1850.39) 2521.26,1850.39 2521.26,1927.26 2562.5,1968.5 4388.19,1968.5 ; 2162,0 2203.15,41.15 2203.15,118.11 cw(c2362.2,118.11) 2521.26,118.11 2521.26,40.74 2561,1 4388.48,1 ; 4388.83,1968.5 ccw(c4723.48,1968) 4724.41,1633.36 ; 4389.84,0 cw(c4724.48,1) 4724.41,335.65 ; 4723.48,336.98 4723.48,1632.95
  text ".Layer_Name" at 577,-858.49 h60
Drill Guide:
  text ".Layer_Name" at 577,-858.49 h60
M1 Board Outline:
  lines w4: 2161.42,0 335.17,0 ccw(c0.52,0) 0,334.65 0,1633.36 ccw(c1.52,1968) 336.17,1968.5 2162.5,1968.5 2203.15,1927.85 2203.15,1850.39 ccw(c2362.2,1850.39) 2521.26,1850.39 2521.26,1927.26 2562.5,1968.5 4388.83,1968.5 ccw(c4723.48,1968) 4724.41,1633.36 4724.41,335.65 ccw(c4724.48,1) 4389.84,0 2562,0 2521.26,40.74 2521.26,118.11 ccw(c2362.2,118.11) 2203.15,118.11 2203.15,41.15 2162,0
  text ".Layer_Name" at 577,-858.49 h60
M2 Board Dimensions:
  rectangle: 125,-400 500,-275
  rectangle: 0,-275 125,-150
  lines w5: 165,988 476,988 ; 787,1296 787,1607 ; 1098,988 1409,988 ; 2240,724 2301,724 ; 2240,1235.81 2301,1235.81 ; 2362,513 2362,574 ; 2362,1024.81 2362,1085.81 ; 2362,1394 2362,1455 ; 2423,724 2484,724 ; 2423,1235.81 2484,1235.81 ; 3735,980 3836,980 ; 3937,782 3937,883 ; 4038,980 4139,980
  lines w7: 0,-275 1000,-275 ; 125,-400 125,-150 ; 250,-400 250,-150 ; 500,-400 500,-150 ; 750,-400 750,-150 ; 0,-400 0,-150 1000,-150 1000,-400 0,-400
  text ".Layer_Name" at 577,-858.49 h60
M3 3D STEP Top:
  text ".Layer_Name" at 577,-858.49 h60
M4 3D STEP Bottom:
  text ".Layer_Name" at 577,-858.49 h60
M5 Assembly Top:
  lines w10: -292,-930.17 6308,-930.17 ; -292,-726.83 6310,-726.83 ; -292,-523.5 -292,-1133.5 3713,-1133.5 6310,-1133.5 6310,-523.5 -291.5,-523.5 -291.5,-1133.5 1284,-1133.5 ; 2173,-1133.5 2173,-523.5 ; 3440,-726.83 3440,-523.5 ; 4280,-726.83 4280,-523.5 ; 4902,-1140 4902,-937.17
  text "COMPONENTS MARKED 'DNP' SHOULD NOT BE POPULATED." at 1153.5,-318.5 h60
  text "ASSEMBLY VARIANT:" at 1153,-434 h60
  text ".VariantName" at 2189,-434 h60
  text "PCB VIEWED FROM TOP SIDE" at -228.5,-655.67 h60
  text "BOARD #:" at 2248,-655.67 h60
  text ".PRJ_Number" at 2793.5,-655.67 h60
  text "REV:" at 3638,-655.67 h60
  text ".PCB_Rev" at 3929.5,-655.67 h60
  text "SVN REV:" at 4476,-655.67 h60
  text ".VersionControl_RevNumber" at 4982,-655.67 h60
  text "PLOT NAME =" at -228.5,-1064.34 h60
  text ".plot_File_Name" at 577,-1064.34 h60
  text "GENERATED    :" at 2250,-1064.34 h60
  text ".Print_Date" at 3119.5,-1064.34 h60
  text ".Print_Time" at 3848.5,-1064.34 h60
  text "TEXAS INSTRUMENTS" at 5113,-1064.34 h60
M6 Assembly Bottom:
  lines w10: -292.5,-727.33 6309.5,-727.33 ; -290.5,-930.67 6309.5,-930.67 ; 1115.5,-1140.5 1115.5,-937.67 ; 1737.5,-727.33 1737.5,-524 ; 2577.5,-727.33 2577.5,-524 ; 3844.5,-1134 3844.5,-524 ; 4733.5,-1134 6309,-1134 6309,-524 -292.5,-524 -292.5,-1134 2304.5,-1134 6309.5,-1134 6309.5,-524
  text "COMPONENTS MARKED 'DNP' SHOULD NOT BE POPULATED." at 6102,-318 h60
  text ".VariantName" at 5058,-434 h60
  text "ASSEMBLY VARIANT:" at 6097,-434 h60
  text ".VersionControl_RevNumber" at 1035.5,-656.17 h60
  text "SVN REV:" at 1541.5,-656.17 h60
  text ".PCB_Rev" at 2088,-656.17 h60
  text "REV:" at 2379.5,-656.17 h60
  text ".PRJ_Number" at 3224,-656.17 h60
  text "BOARD #:" at 3769.5,-656.17 h60
  text "PCB VIEWED FROM BOTTOM SIDE" at 6246,-656.17 h60
  text "TEXAS INSTRUMENTS" at 904.5,-1064.84 h60
  text ".Print_Time" at 2169,-1064.84 h60
  text ".Print_Date" at 2898,-1064.84 h60
  text "GENERATED    :" at 3767.5,-1064.84 h60
  text ".plot_File_Name" at 5440.5,-1064.84 h60
  text "PLOT NAME =" at 6246,-1064.84 h60
M9 Title Sheet:
  drawing of 1178 lines, arcs and shapes, not listed
  text "1" at 739.84,8036.5 h70
  text "2" at 3235.5,8036.5 h70
  text "3" at 5724.84,8036.5 h70
  text "4" at 8231.51,8036.5 h70
  text "5" at 10730.5,8036.5 h70
  text "6" at 13235.5,8036.5 h70
  text "A" at -416.5,6893.5 h70
  text "A" at 14383.5,6893.5 h70
  text "B" at -416.5,4513.5 h70
  text "B" at 14383.5,4513.5 h70
  text "C" at -416.5,2138.5 h70
  text "C" at 14383.5,2138.5 h70
  text "PROJECT TITLE:" at 11343.5,277.5 h45
  text ".PRJ_Title" at 11393.5,144.17 h70
  text "DESIGNED FOR:" at 11343.5,-23.5 h45
  text ".PRJ_Customer" at 11393.5,-163.5 h70
  text "D" at -416.5,-231.5 h70
  text "D" at 14383.5,-231.5 h70
  text "FILE NAME:" at 11343.5,-323.5 h45
  text ".PCB_File_Name_No_Path" at 11393.5,-443.5 h70
  text "Texas Instruments (TI) and/or its licensors do not warrant the accuracy or completeness of this specification" at 6374,-605.34 h45
  text "ENGINEER:" at 11343.5,-613.5 h45
  text "LAYOUT BY:" at 12848.5,-613.5 h45
  text "or any information contained therein. TI and/or its licensors do not warrant that this design will meet" at 6329.01,-718 h45
  text ".PRJ_Engineer" at 11393.5,-768.49 h70
  text ".PCB_Layout" at 12899,-768.49 h70
  text "JMM" at 12830,-800 h80
  text "s  o  l  u  t  i  o  n  s" at 13708,-801 h68
  text "the specifications, will be suitable for your application or fit for any particular purpose, or will operate in" at 6329.01,-830.67 h45
  text ".Layer_Name" at 577,-858.49 h60
  text "ALTIUM DESIGNER VERSION:" at 12848.5,-923.5 h45
  text "an implementation. TI and/or its licensors do not warrant that the design is production worthy. You should" at 6329.01,-943.33 h45
  text "completely validate and test your design implementation to confirm the system functionality for your application." at 6374,-1056 h45
  text ".print_Scale" at 11393.5,-1056.83 h70
  text ".Application_BuildNumber" at 12899,-1056.83 h70
  text "1" at 739.84,-1263.5 h70
  text "2" at 3235.5,-1263.5 h70
  text "3" at 5724.84,-1263.5 h70
  text "4" at 8231.51,-1263.5 h70
  text "5" at 10730.5,-1263.5 h70
  text "6" at 13235.5,-1263.5 h70
M10 Fab Notes:
  drawing of 185 lines, arcs and shapes, not listed
  text "DESIGN INFORMATION" at 12381.02,5910 h60
  text "MIN. TRACK WIDTH:" at 11736.46,5730 h60
  text "5.3" at 12773,5730 h60
  text "MIL" at 12987.46,5730 h60
  text "MIN. CLEARANCE:" at 11736.46,5598 h60
  text "0.2" at 12772.7,5598 h60
  text "mm" at 12987.46,5598 h60
  text "MIN. VIA PAD SIZE:" at 11736.46,5466 h60
  text "20" at 12802.71,5466 h60
  text "MIL" at 12987.46,5466 h60
  text "0.05mm (2MIL)" at 12431.46,5324.29 h60
  text "MINIMUM ANNULAR RING" at 11407.23,5320 h60
  text "EXTERNAL" at 13139.46,5320 h60
  text "PER" at 11607.23,5202 h60
  text "IPC-D-275 CLASS 2 LEVEL C" at 11827.23,5202 h60
  text "MIL, HOLES" at 13315.46,5089.71 h60
  text "+/-" at 12923,5089 h60
  text "+/-" at 13777,5089 h60
  text "REGISTRATION TOLERANCES:" at 11407.23,5084 h60
  text "METAL" at 12607,5084 h60
  text "5" at 13183.2,5084 h60
  text "3" at 14016.2,5084 h60
  text "MIL" at 14132.46,5084 h60
  text "MATERIAL:" at 11332.46,4874.54 h60
  text "FR-4 High Tg" at 12318.9,4734.21 h60
  text "FR-408" at 11753.46,4725.64 h60
  text "X" at 12165.46,4725.64 h60
  text "OTHER" at 13241.46,4725.64 h60
  text "62 MIL (1.6mm) +/-10%" at 12073.56,4562.92 h60
  text "THICKNESS:" at 11407.23,4558.64 h60
  text "X" at 11945.4,4558.64 h60
  text "OTHER" at 13358.46,4558.64 h60
  text "TOLERANCE:" at 11407.23,4400.64 h60
  text "X" at 12246.53,4400.64 h60
  text "ANSI IPC-6012 TYPE 3 CLASS 2" at 12433.48,4400.64 h60
  text "OTHER +/-" at 12433.46,4244.64 h60
  text "BOW & TWIST:" at 11407.23,4087.64 h60
  text "X" at 12246.53,4087.64 h60
  text "ANSI IPC-6012 TYPE 3 CLASS 2" at 12433.48,4087.64 h60
  text "OTHER +/-" at 12433.46,3929.13 h60
  text "DRILLING:" at 11332.46,3790.64 h60
  text "REFERENCE:" at 11407.23,3673.64 h60
  text "X" at 12055.46,3673.64 h60
  text "AS SHOWN" at 12242.46,3673.64 h60
  text "X" at 12956.46,3673.64 h60
  text "NC_DRILL FILES" at 13093.46,3673.64 h60
  text "PTH MIN COPPER THICKNESS:" at 11407.23,3515.64 h60
  text "X" at 12757.46,3515.64 h60
  text "1MIL" at 12894.46,3515.64 h60
  text "OTHER" at 13391.46,3515.64 h60
  text "BOARD FINISH:" at 11332.46,3356.64 h60
  text "SILKSCREEN:" at 11487.68,3238.64 h60
  text "X" at 12436.46,3238.64 h60
  text "TOP" at 12562.46,3238.64 h60
  text "X" at 12946.46,3238.64 h60
  text "BOTTOM" at 13073.46,3238.64 h60
  text "SILKSCREEN COLOR:" at 11487.68,3071.64 h60
  text "X" at 12435.42,3071.64 h60
  text "WHITE" at 12562.46,3071.64 h60
  text "OTHER" at 13073.46,3071.64 h60
  text "SOLDER RESIST COLOR:" at 11487.68,2901.64 h60
  text "X" at 12055.42,2742.44 h60
  text "GREEN" at 12182.46,2742.44 h60
  text "BLUE" at 12773.46,2742.44 h60
  text "OTHER" at 13311.46,2742.44 h60
  text "IMMERSION GOLD (ENIG)" at 12393.46,2553.92 h60
  text "ENEPIG" at 13731,2550.64 h60
  text "SURFACE FINISH:" at 11332.46,2549.64 h60
  text "X" at 12206.51,2549.64 h60
  text "IMM. TIN/SILVER OR EQUIV" at 11662,2392.64 h60
  text "OTHER" at 13093.46,2392.64 h60
  text "ARRAY/PANEL:" at 11332.46,2213.64 h60
  text "CUT AND TRIM PER MECH LAYER 1" at 12393.46,2209.35 h60
  text "N.C. ROUTE" at 12393.46,2057.64 h60
  text "X" at 13072.46,2057.64 h60
  text "V. SCORE" at 13259.46,2057.64 h60
  text "CERTIFICATION:" at 11332.46,1920.64 h60
  text "MATERIALS AND WORKMANSHIP FOR ALL PCBS" at 12057.46,1920.64 h60
  text "TO MEET OR EXCEED THE REQUIREMENTS OF:" at 12057.46,1822.64 h60
  text "X" at 11683.96,1686.13 h60
  text "ANSI IPC-A-600F CLASS ->" at 11822.96,1686.13 h60
  text "X" at 13462.02,1686.13 h60
  text "2" at 13580.96,1686.14 h60
  text "1" at 13265.96,1684.64 h60
  text "3" at 13934.96,1684.64 h60
  text "X" at 11686.02,1526.64 h60
  text "UL 94V-0" at 11822.96,1526.64 h60
  text "X" at 12498.02,1526.64 h60
  text "RoHS" at 12634.96,1526.64 h60
  text "OTHER" at 13279.36,1526.64 h60
  text "PER ORDER" at 13676.42,1526.64 h60
  text "ADDITIONAL REQUIREMENTS:" at 11332.46,1385.64 h60
  text "MICROSECTION:" at 11407.23,1270.64 h60
  text "YES" at 12312.96,1270.64 h60
  text "REQUIRED" at 13174.46,1114.49 h60
  text "BARE BOARD ELEC. TEST:" at 11407.23,1111.64 h60
  text "NONE" at 12712.96,1111.64 h60
  text "X" at 13047.46,1111.64 h60
  text "PER ORDER" at 13766.46,1111.64 h60
  text "MANUFACTURER'S UL:" at 11407.23,954.64 h60
  text "RAIL" at 12572.96,950.35 h60
  text "METAL" at 13064.77,950.35 h60
  text "X" at 13440,950 h60
  text "SILK" at 13576.46,950.35 h60
  text ".Layer_Name" at 577,-858.49 h60
M11 Gerber Information:
  lines w10: -292,-930.17 6308,-930.17 ; -292,-726.83 6310,-726.83 ; -292,-523.5 -292,-1133.5 3713,-1133.5 6310,-1133.5 6310,-523.5 -291.5,-523.5 -291.5,-1133.5 1284,-1133.5 ; 2173,-1133.5 2173,-523.5 ; 3440,-726.83 3440,-523.5 ; 4280,-726.83 4280,-523.5 ; 4902,-1140 4902,-937.17
  text "ALL ARTWORK VIEWED FROM TOP SIDE" at -228.5,-655.67 h60
  text "BOARD #:" at 2248,-655.67 h60
  text ".PRJ_Number" at 2793.5,-655.67 h60
  text "REV:" at 3638,-655.67 h60
  text ".PCB_Rev" at 3929.5,-655.67 h60
  text "SVN REV:" at 4476,-655.67 h60
  text ".VersionControl_RevNumber" at 4982,-655.67 h60
  text "LAYER NAME =" at -228.5,-858.49 h60
  text "PLOT NAME =" at -228.5,-1064.34 h60
  text ".plot_File_Name" at 577,-1064.34 h60
  text "GENERATED    :" at 2250,-1064.34 h60
  text ".Print_Date" at 3119.5,-1064.34 h60
  text ".Print_Time" at 3848.5,-1064.34 h60
  text "TEXAS INSTRUMENTS" at 5113,-1064.34 h60
M12 Stackup:
  drawing of 295 lines, arcs and shapes, not listed
  text "Layer" at 9315,7845 h60
  text "Name" at 9724.91,7845 h60
  text "Material" at 11134.5,7845 h60
  text "Thickness" at 11994.27,7845 h60
  text "Constant" at 12644.1,7845 h60
  text "Board Layer Stack" at 13213.97,7845 h60
  text "1" at 9315,7725 h60
  text "Top Overlay" at 9724.91,7725 h60
  text "2" at 9315,7605 h60
  text "Top Solder" at 9724.91,7605 h60
  text "Solder Resist" at 11134.5,7605 h60
  text "0.40mil" at 11994.27,7605 h60
  text "3.5" at 12644.1,7605 h60
  text "3" at 9315,7485 h60
  text "Layer 1 - Top Layer" at 9724.91,7485 h60
  text "Copper" at 11134.5,7485 h60
  text "1.40mil" at 11994.27,7485 h60
  text "4" at 9315,7365 h60
  text "Dielectric1" at 9724.91,7365 h60
  text "370HR" at 11134.5,7365 h60
  text "5.20mil" at 11994.27,7365 h60
  text "4.2" at 12644.1,7365 h60
  text "5" at 9315,7245 h60
  text "Layer 2 - GND" at 9724.91,7245 h60
  text "Copper" at 11134.5,7245 h60
  text "1.40mil" at 11994.27,7245 h60
  text "6" at 9315,7125 h60
  text "Dielectric3" at 9724.91,7125 h60
  text "370HR" at 11134.5,7125 h60
  text "43.00mil" at 11994.27,7125 h60
  text "4.2" at 12644.1,7125 h60
  text "7" at 9315,7005 h60
  text "Layer 3 - Power" at 9724.91,7005 h60
  text "Copper" at 11134.5,7005 h60
  text "1.40mil" at 11994.27,7005 h60
  text "8" at 9315,6885 h60
  text "Dielectric2" at 9724.91,6885 h60
  text "370HR" at 11134.5,6885 h60
  text "5.20mil" at 11994.27,6885 h60
  text "4.2" at 12644.1,6885 h60
  text "9" at 9315,6765 h60
  text "Layer 4 - Bottom Layer" at 9724.91,6765 h60
  text "Copper" at 11134.5,6765 h60
  text "1.40mil" at 11994.27,6765 h60
  text "10" at 9315,6645 h60
  text "Bottom Solder" at 9724.91,6645 h60
  text "Solder Resist" at 11134.5,6645 h60
  text "0.40mil" at 11994.27,6645 h60
  text "3.5" at 12644.1,6645 h60
  text "11" at 9315,6525 h60
  text "Bottom Overlay" at 9724.91,6525 h60
  text ".Layer_Name" at 577,-858.49 h60
M13 Component Bodies Top:
  text ".Layer_Name" at 577,-858.49 h60
M14 Component Bodies Bottom:
  text ".Layer_Name" at 577,-858.49 h60
M15 Courtyards Top:
  text ".Layer_Name" at 577,-858.49 h60
M16 Courtyards Bottom:
  text ".Layer_Name" at 577,-858.49 h60
Drill Drawing:
  circle w1: c5732.8,2391.37 r24.91
  lines w1: 5707.89,2266.82 5757.71,2266.82 5732.8,2217 5707.89,2266.82 ; 5707.89,2515.92 5757.71,2515.92 5757.71,2565.74 5707.89,2565.74 5707.89,2515.92
  lines w12: 5640,2172.17 7759.4,2172.17 ; 5640,2620.54 7759.4,2620.54 ; 6010.67,2022.71 6010.67,2770 ; 6367.78,2022.71 6367.78,2770 ; 7029.79,2022.71 7029.79,2770 ; 7314.14,2022.71 7314.14,2770 ; 5640,2022.71 7759.4,2022.71 7759.4,2770 5640,2770 5640,2022.71
  text "Symbol" at 5729.68,2665.38 h72
  text "Quantity" at 6055.51,2665.38 h72
  text "Finished Hole Size" at 6412.62,2665.38 h72
  text "Plated" at 7074.62,2665.38 h72
  text "Hole Type" at 7358.98,2665.38 h72
  text "17" at 6055.51,2515.92 h60
  text "6.00mil (0.152mm)" at 6412.62,2515.92 h60
  text "PTH" at 7074.62,2515.92 h60
  text "Round" at 7358.98,2515.92 h60
  text "18" at 6055.51,2366.46 h60
  text "7.87mil (0.200mm)" at 6412.62,2366.46 h60
  text "PTH" at 7074.62,2366.46 h60
  text "Round" at 7358.98,2366.46 h60
  text "255" at 6055.51,2217 h60
  text "10.00mil (0.254mm)" at 6412.62,2217 h60
  text "PTH" at 7074.62,2217 h60
  text "Round" at 7358.98,2217 h60
  text "290 Total" at 6055.51,2067.54 h60
  text ".Layer_Name" at 577,-858.49 h60

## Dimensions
4389.84,0 to 4388.83,1968.5 on M2 Board Dimensions
0,334.65 to 4724.41,335.65 on M2 Board Dimensions
0,-400 to 1000,-400 on M2 Board Dimensions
